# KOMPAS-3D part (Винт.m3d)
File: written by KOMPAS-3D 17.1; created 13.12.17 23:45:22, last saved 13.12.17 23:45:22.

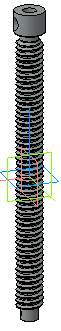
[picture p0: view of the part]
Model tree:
1. Операция без истории:1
